VERSION 5.8 ;
BUSBITCHARS "[]" ;
DIVIDERCHAR "/" ;
UNITS
    DATABASE MICRONS 1000 ;
END UNITS

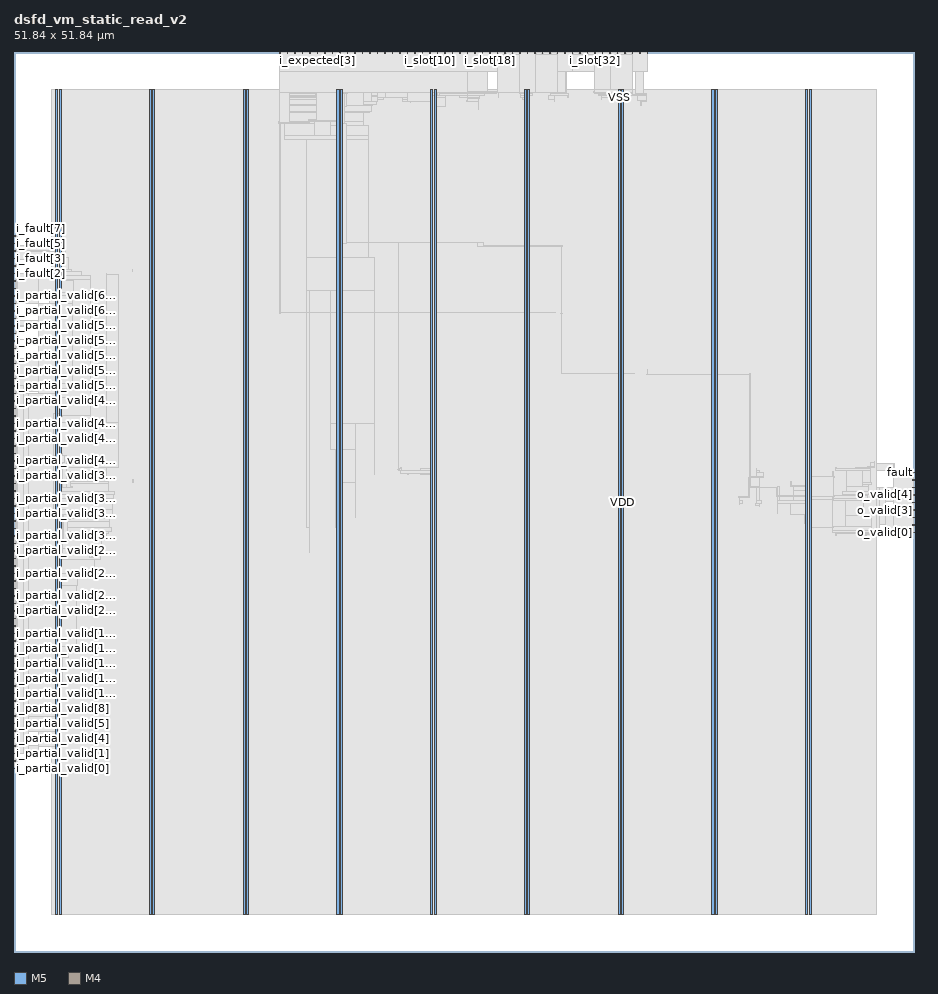
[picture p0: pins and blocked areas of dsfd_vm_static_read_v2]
MACRO dsfd_vm_static_read_v2
  FOREIGN dsfd_vm_static_read_v2 0 0 ;
  CLASS BLOCK ;
  SIZE 51.84 BY 51.84 ;
  PIN ck
    DIRECTION INPUT ;
    USE SIGNAL ;
    PORT
      LAYER M5 ;
        RECT  15.312 51.756 15.336 51.84 ;
    END
  END ck
  PIN fault
    DIRECTION OUTPUT ;
    USE SIGNAL ;
    PORT
      LAYER M4 ;
        RECT  51.756 27.6 51.84 27.624 ;
    END
  END fault
  PIN i_expected[0]
    DIRECTION INPUT ;
    USE SIGNAL ;
    PORT
      LAYER M5 ;
        RECT  16.176 51.756 16.2 51.84 ;
    END
  END i_expected[0]
  PIN i_expected[1]
    DIRECTION INPUT ;
    USE SIGNAL ;
    PORT
      LAYER M5 ;
        RECT  16.608 51.756 16.632 51.84 ;
    END
  END i_expected[1]
  PIN i_expected[2]
    DIRECTION INPUT ;
    USE SIGNAL ;
    PORT
      LAYER M5 ;
        RECT  17.04 51.756 17.064 51.84 ;
    END
  END i_expected[2]
  PIN i_expected[3]
    DIRECTION INPUT ;
    USE SIGNAL ;
    PORT
      LAYER M5 ;
        RECT  17.472 51.756 17.496 51.84 ;
    END
  END i_expected[3]
  PIN i_expected[4]
    DIRECTION INPUT ;
    USE SIGNAL ;
    PORT
      LAYER M5 ;
        RECT  17.904 51.756 17.928 51.84 ;
    END
  END i_expected[4]
  PIN i_expected[5]
    DIRECTION INPUT ;
    USE SIGNAL ;
    PORT
      LAYER M5 ;
        RECT  18.336 51.756 18.36 51.84 ;
    END
  END i_expected[5]
  PIN i_expected[6]
    DIRECTION INPUT ;
    USE SIGNAL ;
    PORT
      LAYER M5 ;
        RECT  18.768 51.756 18.792 51.84 ;
    END
  END i_expected[6]
  PIN i_expected[7]
    DIRECTION INPUT ;
    USE SIGNAL ;
    PORT
      LAYER M5 ;
        RECT  19.2 51.756 19.224 51.84 ;
    END
  END i_expected[7]
  PIN i_fault[0]
    DIRECTION INPUT ;
    USE SIGNAL ;
    PORT
      LAYER M4 ;
        RECT  0 38.208 0.084 38.232 ;
    END
  END i_fault[0]
  PIN i_fault[1]
    DIRECTION INPUT ;
    USE SIGNAL ;
    PORT
      LAYER M4 ;
        RECT  0 38.64 0.084 38.664 ;
    END
  END i_fault[1]
  PIN i_fault[2]
    DIRECTION INPUT ;
    USE SIGNAL ;
    PORT
      LAYER M4 ;
        RECT  0 39.072 0.084 39.096 ;
    END
  END i_fault[2]
  PIN i_fault[3]
    DIRECTION INPUT ;
    USE SIGNAL ;
    PORT
      LAYER M4 ;
        RECT  0 39.504 0.084 39.528 ;
    END
  END i_fault[3]
  PIN i_fault[4]
    DIRECTION INPUT ;
    USE SIGNAL ;
    PORT
      LAYER M4 ;
        RECT  0 39.936 0.084 39.96 ;
    END
  END i_fault[4]
  PIN i_fault[5]
    DIRECTION INPUT ;
    USE SIGNAL ;
    PORT
      LAYER M4 ;
        RECT  0 40.368 0.084 40.392 ;
    END
  END i_fault[5]
  PIN i_fault[6]
    DIRECTION INPUT ;
    USE SIGNAL ;
    PORT
      LAYER M4 ;
        RECT  0 40.8 0.084 40.824 ;
    END
  END i_fault[6]
  PIN i_fault[7]
    DIRECTION INPUT ;
    USE SIGNAL ;
    PORT
      LAYER M4 ;
        RECT  0 41.232 0.084 41.256 ;
    END
  END i_fault[7]
  PIN i_partial_valid[0]
    DIRECTION INPUT ;
    USE SIGNAL ;
    PORT
      LAYER M4 ;
        RECT  0 10.56 0.084 10.584 ;
    END
  END i_partial_valid[0]
  PIN i_partial_valid[10]
    DIRECTION INPUT ;
    USE SIGNAL ;
    PORT
      LAYER M4 ;
        RECT  0 14.88 0.084 14.904 ;
    END
  END i_partial_valid[10]
  PIN i_partial_valid[11]
    DIRECTION INPUT ;
    USE SIGNAL ;
    PORT
      LAYER M4 ;
        RECT  0 15.312 0.084 15.336 ;
    END
  END i_partial_valid[11]
  PIN i_partial_valid[12]
    DIRECTION INPUT ;
    USE SIGNAL ;
    PORT
      LAYER M4 ;
        RECT  0 15.744 0.084 15.768 ;
    END
  END i_partial_valid[12]
  PIN i_partial_valid[13]
    DIRECTION INPUT ;
    USE SIGNAL ;
    PORT
      LAYER M4 ;
        RECT  0 16.176 0.084 16.2 ;
    END
  END i_partial_valid[13]
  PIN i_partial_valid[14]
    DIRECTION INPUT ;
    USE SIGNAL ;
    PORT
      LAYER M4 ;
        RECT  0 16.608 0.084 16.632 ;
    END
  END i_partial_valid[14]
  PIN i_partial_valid[15]
    DIRECTION INPUT ;
    USE SIGNAL ;
    PORT
      LAYER M4 ;
        RECT  0 17.04 0.084 17.064 ;
    END
  END i_partial_valid[15]
  PIN i_partial_valid[16]
    DIRECTION INPUT ;
    USE SIGNAL ;
    PORT
      LAYER M4 ;
        RECT  0 17.472 0.084 17.496 ;
    END
  END i_partial_valid[16]
  PIN i_partial_valid[17]
    DIRECTION INPUT ;
    USE SIGNAL ;
    PORT
      LAYER M4 ;
        RECT  0 17.904 0.084 17.928 ;
    END
  END i_partial_valid[17]
  PIN i_partial_valid[18]
    DIRECTION INPUT ;
    USE SIGNAL ;
    PORT
      LAYER M4 ;
        RECT  0 18.336 0.084 18.36 ;
    END
  END i_partial_valid[18]
  PIN i_partial_valid[19]
    DIRECTION INPUT ;
    USE SIGNAL ;
    PORT
      LAYER M4 ;
        RECT  0 18.768 0.084 18.792 ;
    END
  END i_partial_valid[19]
  PIN i_partial_valid[1]
    DIRECTION INPUT ;
    USE SIGNAL ;
    PORT
      LAYER M4 ;
        RECT  0 10.992 0.084 11.016 ;
    END
  END i_partial_valid[1]
  PIN i_partial_valid[20]
    DIRECTION INPUT ;
    USE SIGNAL ;
    PORT
      LAYER M4 ;
        RECT  0 19.2 0.084 19.224 ;
    END
  END i_partial_valid[20]
  PIN i_partial_valid[21]
    DIRECTION INPUT ;
    USE SIGNAL ;
    PORT
      LAYER M4 ;
        RECT  0 19.632 0.084 19.656 ;
    END
  END i_partial_valid[21]
  PIN i_partial_valid[22]
    DIRECTION INPUT ;
    USE SIGNAL ;
    PORT
      LAYER M4 ;
        RECT  0 20.064 0.084 20.088 ;
    END
  END i_partial_valid[22]
  PIN i_partial_valid[23]
    DIRECTION INPUT ;
    USE SIGNAL ;
    PORT
      LAYER M4 ;
        RECT  0 20.496 0.084 20.52 ;
    END
  END i_partial_valid[23]
  PIN i_partial_valid[24]
    DIRECTION INPUT ;
    USE SIGNAL ;
    PORT
      LAYER M4 ;
        RECT  0 20.928 0.084 20.952 ;
    END
  END i_partial_valid[24]
  PIN i_partial_valid[25]
    DIRECTION INPUT ;
    USE SIGNAL ;
    PORT
      LAYER M4 ;
        RECT  0 21.36 0.084 21.384 ;
    END
  END i_partial_valid[25]
  PIN i_partial_valid[26]
    DIRECTION INPUT ;
    USE SIGNAL ;
    PORT
      LAYER M4 ;
        RECT  0 21.792 0.084 21.816 ;
    END
  END i_partial_valid[26]
  PIN i_partial_valid[27]
    DIRECTION INPUT ;
    USE SIGNAL ;
    PORT
      LAYER M4 ;
        RECT  0 22.224 0.084 22.248 ;
    END
  END i_partial_valid[27]
  PIN i_partial_valid[28]
    DIRECTION INPUT ;
    USE SIGNAL ;
    PORT
      LAYER M4 ;
        RECT  0 22.656 0.084 22.68 ;
    END
  END i_partial_valid[28]
  PIN i_partial_valid[29]
    DIRECTION INPUT ;
    USE SIGNAL ;
    PORT
      LAYER M4 ;
        RECT  0 23.088 0.084 23.112 ;
    END
  END i_partial_valid[29]
  PIN i_partial_valid[2]
    DIRECTION INPUT ;
    USE SIGNAL ;
    PORT
      LAYER M4 ;
        RECT  0 11.424 0.084 11.448 ;
    END
  END i_partial_valid[2]
  PIN i_partial_valid[30]
    DIRECTION INPUT ;
    USE SIGNAL ;
    PORT
      LAYER M4 ;
        RECT  0 23.52 0.084 23.544 ;
    END
  END i_partial_valid[30]
  PIN i_partial_valid[31]
    DIRECTION INPUT ;
    USE SIGNAL ;
    PORT
      LAYER M4 ;
        RECT  0 23.952 0.084 23.976 ;
    END
  END i_partial_valid[31]
  PIN i_partial_valid[32]
    DIRECTION INPUT ;
    USE SIGNAL ;
    PORT
      LAYER M4 ;
        RECT  0 24.384 0.084 24.408 ;
    END
  END i_partial_valid[32]
  PIN i_partial_valid[33]
    DIRECTION INPUT ;
    USE SIGNAL ;
    PORT
      LAYER M4 ;
        RECT  0 24.816 0.084 24.84 ;
    END
  END i_partial_valid[33]
  PIN i_partial_valid[34]
    DIRECTION INPUT ;
    USE SIGNAL ;
    PORT
      LAYER M4 ;
        RECT  0 25.248 0.084 25.272 ;
    END
  END i_partial_valid[34]
  PIN i_partial_valid[35]
    DIRECTION INPUT ;
    USE SIGNAL ;
    PORT
      LAYER M4 ;
        RECT  0 25.68 0.084 25.704 ;
    END
  END i_partial_valid[35]
  PIN i_partial_valid[36]
    DIRECTION INPUT ;
    USE SIGNAL ;
    PORT
      LAYER M4 ;
        RECT  0 26.112 0.084 26.136 ;
    END
  END i_partial_valid[36]
  PIN i_partial_valid[37]
    DIRECTION INPUT ;
    USE SIGNAL ;
    PORT
      LAYER M4 ;
        RECT  0 26.544 0.084 26.568 ;
    END
  END i_partial_valid[37]
  PIN i_partial_valid[38]
    DIRECTION INPUT ;
    USE SIGNAL ;
    PORT
      LAYER M4 ;
        RECT  0 26.976 0.084 27 ;
    END
  END i_partial_valid[38]
  PIN i_partial_valid[39]
    DIRECTION INPUT ;
    USE SIGNAL ;
    PORT
      LAYER M4 ;
        RECT  0 27.408 0.084 27.432 ;
    END
  END i_partial_valid[39]
  PIN i_partial_valid[3]
    DIRECTION INPUT ;
    USE SIGNAL ;
    PORT
      LAYER M4 ;
        RECT  0 11.856 0.084 11.88 ;
    END
  END i_partial_valid[3]
  PIN i_partial_valid[40]
    DIRECTION INPUT ;
    USE SIGNAL ;
    PORT
      LAYER M4 ;
        RECT  0 27.84 0.084 27.864 ;
    END
  END i_partial_valid[40]
  PIN i_partial_valid[41]
    DIRECTION INPUT ;
    USE SIGNAL ;
    PORT
      LAYER M4 ;
        RECT  0 28.272 0.084 28.296 ;
    END
  END i_partial_valid[41]
  PIN i_partial_valid[42]
    DIRECTION INPUT ;
    USE SIGNAL ;
    PORT
      LAYER M4 ;
        RECT  0 28.704 0.084 28.728 ;
    END
  END i_partial_valid[42]
  PIN i_partial_valid[43]
    DIRECTION INPUT ;
    USE SIGNAL ;
    PORT
      LAYER M4 ;
        RECT  0 29.136 0.084 29.16 ;
    END
  END i_partial_valid[43]
  PIN i_partial_valid[44]
    DIRECTION INPUT ;
    USE SIGNAL ;
    PORT
      LAYER M4 ;
        RECT  0 29.568 0.084 29.592 ;
    END
  END i_partial_valid[44]
  PIN i_partial_valid[45]
    DIRECTION INPUT ;
    USE SIGNAL ;
    PORT
      LAYER M4 ;
        RECT  0 30 0.084 30.024 ;
    END
  END i_partial_valid[45]
  PIN i_partial_valid[46]
    DIRECTION INPUT ;
    USE SIGNAL ;
    PORT
      LAYER M4 ;
        RECT  0 30.432 0.084 30.456 ;
    END
  END i_partial_valid[46]
  PIN i_partial_valid[47]
    DIRECTION INPUT ;
    USE SIGNAL ;
    PORT
      LAYER M4 ;
        RECT  0 30.864 0.084 30.888 ;
    END
  END i_partial_valid[47]
  PIN i_partial_valid[48]
    DIRECTION INPUT ;
    USE SIGNAL ;
    PORT
      LAYER M4 ;
        RECT  0 31.296 0.084 31.32 ;
    END
  END i_partial_valid[48]
  PIN i_partial_valid[49]
    DIRECTION INPUT ;
    USE SIGNAL ;
    PORT
      LAYER M4 ;
        RECT  0 31.728 0.084 31.752 ;
    END
  END i_partial_valid[49]
  PIN i_partial_valid[4]
    DIRECTION INPUT ;
    USE SIGNAL ;
    PORT
      LAYER M4 ;
        RECT  0 12.288 0.084 12.312 ;
    END
  END i_partial_valid[4]
  PIN i_partial_valid[50]
    DIRECTION INPUT ;
    USE SIGNAL ;
    PORT
      LAYER M4 ;
        RECT  0 32.16 0.084 32.184 ;
    END
  END i_partial_valid[50]
  PIN i_partial_valid[51]
    DIRECTION INPUT ;
    USE SIGNAL ;
    PORT
      LAYER M4 ;
        RECT  0 32.592 0.084 32.616 ;
    END
  END i_partial_valid[51]
  PIN i_partial_valid[52]
    DIRECTION INPUT ;
    USE SIGNAL ;
    PORT
      LAYER M4 ;
        RECT  0 33.024 0.084 33.048 ;
    END
  END i_partial_valid[52]
  PIN i_partial_valid[53]
    DIRECTION INPUT ;
    USE SIGNAL ;
    PORT
      LAYER M4 ;
        RECT  0 33.456 0.084 33.48 ;
    END
  END i_partial_valid[53]
  PIN i_partial_valid[54]
    DIRECTION INPUT ;
    USE SIGNAL ;
    PORT
      LAYER M4 ;
        RECT  0 33.888 0.084 33.912 ;
    END
  END i_partial_valid[54]
  PIN i_partial_valid[55]
    DIRECTION INPUT ;
    USE SIGNAL ;
    PORT
      LAYER M4 ;
        RECT  0 34.32 0.084 34.344 ;
    END
  END i_partial_valid[55]
  PIN i_partial_valid[56]
    DIRECTION INPUT ;
    USE SIGNAL ;
    PORT
      LAYER M4 ;
        RECT  0 34.752 0.084 34.776 ;
    END
  END i_partial_valid[56]
  PIN i_partial_valid[57]
    DIRECTION INPUT ;
    USE SIGNAL ;
    PORT
      LAYER M4 ;
        RECT  0 35.184 0.084 35.208 ;
    END
  END i_partial_valid[57]
  PIN i_partial_valid[58]
    DIRECTION INPUT ;
    USE SIGNAL ;
    PORT
      LAYER M4 ;
        RECT  0 35.616 0.084 35.64 ;
    END
  END i_partial_valid[58]
  PIN i_partial_valid[59]
    DIRECTION INPUT ;
    USE SIGNAL ;
    PORT
      LAYER M4 ;
        RECT  0 36.048 0.084 36.072 ;
    END
  END i_partial_valid[59]
  PIN i_partial_valid[5]
    DIRECTION INPUT ;
    USE SIGNAL ;
    PORT
      LAYER M4 ;
        RECT  0 12.72 0.084 12.744 ;
    END
  END i_partial_valid[5]
  PIN i_partial_valid[60]
    DIRECTION INPUT ;
    USE SIGNAL ;
    PORT
      LAYER M4 ;
        RECT  0 36.48 0.084 36.504 ;
    END
  END i_partial_valid[60]
  PIN i_partial_valid[61]
    DIRECTION INPUT ;
    USE SIGNAL ;
    PORT
      LAYER M4 ;
        RECT  0 36.912 0.084 36.936 ;
    END
  END i_partial_valid[61]
  PIN i_partial_valid[62]
    DIRECTION INPUT ;
    USE SIGNAL ;
    PORT
      LAYER M4 ;
        RECT  0 37.344 0.084 37.368 ;
    END
  END i_partial_valid[62]
  PIN i_partial_valid[63]
    DIRECTION INPUT ;
    USE SIGNAL ;
    PORT
      LAYER M4 ;
        RECT  0 37.776 0.084 37.8 ;
    END
  END i_partial_valid[63]
  PIN i_partial_valid[6]
    DIRECTION INPUT ;
    USE SIGNAL ;
    PORT
      LAYER M4 ;
        RECT  0 13.152 0.084 13.176 ;
    END
  END i_partial_valid[6]
  PIN i_partial_valid[7]
    DIRECTION INPUT ;
    USE SIGNAL ;
    PORT
      LAYER M4 ;
        RECT  0 13.584 0.084 13.608 ;
    END
  END i_partial_valid[7]
  PIN i_partial_valid[8]
    DIRECTION INPUT ;
    USE SIGNAL ;
    PORT
      LAYER M4 ;
        RECT  0 14.016 0.084 14.04 ;
    END
  END i_partial_valid[8]
  PIN i_partial_valid[9]
    DIRECTION INPUT ;
    USE SIGNAL ;
    PORT
      LAYER M4 ;
        RECT  0 14.448 0.084 14.472 ;
    END
  END i_partial_valid[9]
  PIN i_slot[0]
    DIRECTION INPUT ;
    USE SIGNAL ;
    PORT
      LAYER M5 ;
        RECT  19.632 51.756 19.656 51.84 ;
    END
  END i_slot[0]
  PIN i_slot[10]
    DIRECTION INPUT ;
    USE SIGNAL ;
    PORT
      LAYER M5 ;
        RECT  23.952 51.756 23.976 51.84 ;
    END
  END i_slot[10]
  PIN i_slot[11]
    DIRECTION INPUT ;
    USE SIGNAL ;
    PORT
      LAYER M5 ;
        RECT  24.384 51.756 24.408 51.84 ;
    END
  END i_slot[11]
  PIN i_slot[12]
    DIRECTION INPUT ;
    USE SIGNAL ;
    PORT
      LAYER M5 ;
        RECT  24.816 51.756 24.84 51.84 ;
    END
  END i_slot[12]
  PIN i_slot[13]
    DIRECTION INPUT ;
    USE SIGNAL ;
    PORT
      LAYER M5 ;
        RECT  25.248 51.756 25.272 51.84 ;
    END
  END i_slot[13]
  PIN i_slot[14]
    DIRECTION INPUT ;
    USE SIGNAL ;
    PORT
      LAYER M5 ;
        RECT  25.68 51.756 25.704 51.84 ;
    END
  END i_slot[14]
  PIN i_slot[15]
    DIRECTION INPUT ;
    USE SIGNAL ;
    PORT
      LAYER M5 ;
        RECT  26.112 51.756 26.136 51.84 ;
    END
  END i_slot[15]
  PIN i_slot[16]
    DIRECTION INPUT ;
    USE SIGNAL ;
    PORT
      LAYER M5 ;
        RECT  26.544 51.756 26.568 51.84 ;
    END
  END i_slot[16]
  PIN i_slot[17]
    DIRECTION INPUT ;
    USE SIGNAL ;
    PORT
      LAYER M5 ;
        RECT  26.976 51.756 27 51.84 ;
    END
  END i_slot[17]
  PIN i_slot[18]
    DIRECTION INPUT ;
    USE SIGNAL ;
    PORT
      LAYER M5 ;
        RECT  27.408 51.756 27.432 51.84 ;
    END
  END i_slot[18]
  PIN i_slot[19]
    DIRECTION INPUT ;
    USE SIGNAL ;
    PORT
      LAYER M5 ;
        RECT  27.84 51.756 27.864 51.84 ;
    END
  END i_slot[19]
  PIN i_slot[1]
    DIRECTION INPUT ;
    USE SIGNAL ;
    PORT
      LAYER M5 ;
        RECT  20.064 51.756 20.088 51.84 ;
    END
  END i_slot[1]
  PIN i_slot[20]
    DIRECTION INPUT ;
    USE SIGNAL ;
    PORT
      LAYER M5 ;
        RECT  28.272 51.756 28.296 51.84 ;
    END
  END i_slot[20]
  PIN i_slot[21]
    DIRECTION INPUT ;
    USE SIGNAL ;
    PORT
      LAYER M5 ;
        RECT  28.704 51.756 28.728 51.84 ;
    END
  END i_slot[21]
  PIN i_slot[22]
    DIRECTION INPUT ;
    USE SIGNAL ;
    PORT
      LAYER M5 ;
        RECT  29.136 51.756 29.16 51.84 ;
    END
  END i_slot[22]
  PIN i_slot[23]
    DIRECTION INPUT ;
    USE SIGNAL ;
    PORT
      LAYER M5 ;
        RECT  29.568 51.756 29.592 51.84 ;
    END
  END i_slot[23]
  PIN i_slot[24]
    DIRECTION INPUT ;
    USE SIGNAL ;
    PORT
      LAYER M5 ;
        RECT  30 51.756 30.024 51.84 ;
    END
  END i_slot[24]
  PIN i_slot[25]
    DIRECTION INPUT ;
    USE SIGNAL ;
    PORT
      LAYER M5 ;
        RECT  30.432 51.756 30.456 51.84 ;
    END
  END i_slot[25]
  PIN i_slot[26]
    DIRECTION INPUT ;
    USE SIGNAL ;
    PORT
      LAYER M5 ;
        RECT  30.864 51.756 30.888 51.84 ;
    END
  END i_slot[26]
  PIN i_slot[27]
    DIRECTION INPUT ;
    USE SIGNAL ;
    PORT
      LAYER M5 ;
        RECT  31.296 51.756 31.32 51.84 ;
    END
  END i_slot[27]
  PIN i_slot[28]
    DIRECTION INPUT ;
    USE SIGNAL ;
    PORT
      LAYER M5 ;
        RECT  31.728 51.756 31.752 51.84 ;
    END
  END i_slot[28]
  PIN i_slot[29]
    DIRECTION INPUT ;
    USE SIGNAL ;
    PORT
      LAYER M5 ;
        RECT  32.16 51.756 32.184 51.84 ;
    END
  END i_slot[29]
  PIN i_slot[2]
    DIRECTION INPUT ;
    USE SIGNAL ;
    PORT
      LAYER M5 ;
        RECT  20.496 51.756 20.52 51.84 ;
    END
  END i_slot[2]
  PIN i_slot[30]
    DIRECTION INPUT ;
    USE SIGNAL ;
    PORT
      LAYER M5 ;
        RECT  32.592 51.756 32.616 51.84 ;
    END
  END i_slot[30]
  PIN i_slot[31]
    DIRECTION INPUT ;
    USE SIGNAL ;
    PORT
      LAYER M5 ;
        RECT  33.024 51.756 33.048 51.84 ;
    END
  END i_slot[31]
  PIN i_slot[32]
    DIRECTION INPUT ;
    USE SIGNAL ;
    PORT
      LAYER M5 ;
        RECT  33.456 51.756 33.48 51.84 ;
    END
  END i_slot[32]
  PIN i_slot[33]
    DIRECTION INPUT ;
    USE SIGNAL ;
    PORT
      LAYER M5 ;
        RECT  33.888 51.756 33.912 51.84 ;
    END
  END i_slot[33]
  PIN i_slot[34]
    DIRECTION INPUT ;
    USE SIGNAL ;
    PORT
      LAYER M5 ;
        RECT  34.32 51.756 34.344 51.84 ;
    END
  END i_slot[34]
  PIN i_slot[35]
    DIRECTION INPUT ;
    USE SIGNAL ;
    PORT
      LAYER M5 ;
        RECT  34.752 51.756 34.776 51.84 ;
    END
  END i_slot[35]
  PIN i_slot[36]
    DIRECTION INPUT ;
    USE SIGNAL ;
    PORT
      LAYER M5 ;
        RECT  35.184 51.756 35.208 51.84 ;
    END
  END i_slot[36]
  PIN i_slot[37]
    DIRECTION INPUT ;
    USE SIGNAL ;
    PORT
      LAYER M5 ;
        RECT  35.616 51.756 35.64 51.84 ;
    END
  END i_slot[37]
  PIN i_slot[38]
    DIRECTION INPUT ;
    USE SIGNAL ;
    PORT
      LAYER M5 ;
        RECT  36.048 51.756 36.072 51.84 ;
    END
  END i_slot[38]
  PIN i_slot[39]
    DIRECTION INPUT ;
    USE SIGNAL ;
    PORT
      LAYER M5 ;
        RECT  36.48 51.756 36.504 51.84 ;
    END
  END i_slot[39]
  PIN i_slot[3]
    DIRECTION INPUT ;
    USE SIGNAL ;
    PORT
      LAYER M5 ;
        RECT  20.928 51.756 20.952 51.84 ;
    END
  END i_slot[3]
  PIN i_slot[4]
    DIRECTION INPUT ;
    USE SIGNAL ;
    PORT
      LAYER M5 ;
        RECT  21.36 51.756 21.384 51.84 ;
    END
  END i_slot[4]
  PIN i_slot[5]
    DIRECTION INPUT ;
    USE SIGNAL ;
    PORT
      LAYER M5 ;
        RECT  21.792 51.756 21.816 51.84 ;
    END
  END i_slot[5]
  PIN i_slot[6]
    DIRECTION INPUT ;
    USE SIGNAL ;
    PORT
      LAYER M5 ;
        RECT  22.224 51.756 22.248 51.84 ;
    END
  END i_slot[6]
  PIN i_slot[7]
    DIRECTION INPUT ;
    USE SIGNAL ;
    PORT
      LAYER M5 ;
        RECT  22.656 51.756 22.68 51.84 ;
    END
  END i_slot[7]
  PIN i_slot[8]
    DIRECTION INPUT ;
    USE SIGNAL ;
    PORT
      LAYER M5 ;
        RECT  23.088 51.756 23.112 51.84 ;
    END
  END i_slot[8]
  PIN i_slot[9]
    DIRECTION INPUT ;
    USE SIGNAL ;
    PORT
      LAYER M5 ;
        RECT  23.52 51.756 23.544 51.84 ;
    END
  END i_slot[9]
  PIN o_valid[0]
    DIRECTION OUTPUT ;
    USE SIGNAL ;
    PORT
      LAYER M4 ;
        RECT  51.756 24.144 51.84 24.168 ;
    END
  END o_valid[0]
  PIN o_valid[1]
    DIRECTION OUTPUT ;
    USE SIGNAL ;
    PORT
      LAYER M4 ;
        RECT  51.756 24.576 51.84 24.6 ;
    END
  END o_valid[1]
  PIN o_valid[2]
    DIRECTION OUTPUT ;
    USE SIGNAL ;
    PORT
      LAYER M4 ;
        RECT  51.756 25.008 51.84 25.032 ;
    END
  END o_valid[2]
  PIN o_valid[3]
    DIRECTION OUTPUT ;
    USE SIGNAL ;
    PORT
      LAYER M4 ;
        RECT  51.756 25.44 51.84 25.464 ;
    END
  END o_valid[3]
  PIN o_valid[4]
    DIRECTION OUTPUT ;
    USE SIGNAL ;
    PORT
      LAYER M4 ;
        RECT  51.756 25.872 51.84 25.896 ;
    END
  END o_valid[4]
  PIN o_valid[5]
    DIRECTION OUTPUT ;
    USE SIGNAL ;
    PORT
      LAYER M4 ;
        RECT  51.756 26.304 51.84 26.328 ;
    END
  END o_valid[5]
  PIN o_valid[6]
    DIRECTION OUTPUT ;
    USE SIGNAL ;
    PORT
      LAYER M4 ;
        RECT  51.756 26.736 51.84 26.76 ;
    END
  END o_valid[6]
  PIN o_valid[7]
    DIRECTION OUTPUT ;
    USE SIGNAL ;
    PORT
      LAYER M4 ;
        RECT  51.756 27.168 51.84 27.192 ;
    END
  END o_valid[7]
  PIN rst_n
    DIRECTION INPUT ;
    USE SIGNAL ;
    PORT
      LAYER M5 ;
        RECT  15.744 51.756 15.768 51.84 ;
    END
  END rst_n
  PIN VDD
    DIRECTION INOUT ;
    USE POWER ;
    PORT
      LAYER M5 ;
        RECT  45.792 2.151 45.912 49.689 ;
        RECT  40.392 2.151 40.512 49.689 ;
        RECT  34.992 2.151 35.112 49.689 ;
        RECT  29.592 2.151 29.712 49.689 ;
        RECT  24.192 2.151 24.312 49.689 ;
        RECT  18.792 2.151 18.912 49.689 ;
        RECT  13.392 2.151 13.512 49.689 ;
        RECT  7.992 2.151 8.112 49.689 ;
        RECT  2.592 2.151 2.712 49.689 ;
    END
  END VDD
  PIN VSS
    DIRECTION INOUT ;
    USE GROUND ;
    PORT
      LAYER M5 ;
        RECT  45.6 2.137 45.72 49.703 ;
        RECT  40.2 2.137 40.32 49.703 ;
        RECT  34.8 2.137 34.92 49.703 ;
        RECT  29.4 2.137 29.52 49.703 ;
        RECT  24 2.137 24.12 49.703 ;
        RECT  18.6 2.137 18.72 49.703 ;
        RECT  13.2 2.137 13.32 49.703 ;
        RECT  7.8 2.137 7.92 49.703 ;
        RECT  2.4 2.137 2.52 49.703 ;
    END
  END VSS
  # OT_OBS_CLOSED layer=M5 d_um=1.536 added=23
  OBS
    LAYER RVTN ;
     RECT  2.16 2.16 49.68 2.295 ;
     RECT  2.16 2.565 49.68 2.835 ;
     RECT  2.16 3.105 49.68 3.375 ;
     RECT  2.16 3.645 49.68 3.915 ;
     RECT  2.16 4.185 49.68 4.455 ;
     RECT  2.16 4.725 49.68 4.995 ;
     RECT  2.16 5.265 49.68 5.535 ;
     RECT  2.16 5.805 49.68 6.075 ;
     RECT  2.16 6.345 49.68 6.615 ;
     RECT  2.16 6.885 49.68 7.155 ;
     RECT  2.16 7.425 49.68 7.695 ;
     RECT  2.16 7.965 49.68 8.235 ;
     RECT  2.16 8.505 49.68 8.775 ;
     RECT  2.16 9.045 49.68 9.315 ;
     RECT  2.16 9.585 49.68 9.855 ;
     RECT  2.16 10.125 49.68 10.395 ;
     RECT  2.16 10.665 49.68 10.935 ;
     RECT  2.16 11.205 49.68 11.475 ;
     RECT  2.16 11.745 49.68 12.015 ;
     RECT  2.16 12.285 49.68 12.555 ;
     RECT  2.16 12.825 49.68 13.095 ;
     RECT  2.16 13.365 49.68 13.635 ;
     RECT  2.16 13.905 49.68 14.175 ;
     RECT  2.16 14.445 49.68 14.715 ;
     RECT  2.16 14.985 49.68 15.255 ;
     RECT  2.16 15.525 49.68 15.795 ;
     RECT  2.16 16.065 49.68 16.335 ;
     RECT  2.16 16.605 49.68 16.875 ;
     RECT  2.16 17.145 49.68 17.415 ;
     RECT  2.16 17.685 49.68 17.955 ;
     RECT  2.16 18.225 49.68 18.495 ;
     RECT  2.16 18.765 49.68 19.035 ;
     RECT  2.16 19.305 49.68 19.575 ;
     RECT  2.16 19.845 49.68 20.115 ;
     RECT  2.16 20.385 49.68 20.655 ;
     RECT  2.16 20.925 49.68 21.195 ;
     RECT  2.16 21.465 49.68 21.735 ;
     RECT  2.16 22.005 49.68 22.275 ;
     RECT  2.16 22.545 49.68 22.815 ;
     RECT  2.16 23.085 49.68 23.355 ;
     RECT  2.16 23.625 49.68 23.895 ;
     RECT  2.16 24.165 49.68 24.435 ;
     RECT  2.16 24.705 49.68 24.975 ;
     RECT  2.16 25.245 49.68 25.515 ;
     RECT  2.16 25.785 49.68 26.055 ;
     RECT  2.16 26.325 49.68 26.595 ;
     RECT  2.16 26.865 49.68 27.135 ;
     RECT  2.16 27.405 49.68 27.675 ;
     RECT  2.16 27.945 49.68 28.215 ;
     RECT  2.16 28.485 49.68 28.755 ;
     RECT  2.16 29.025 49.68 29.295 ;
     RECT  2.16 29.565 49.68 29.835 ;
     RECT  2.16 30.105 49.68 30.375 ;
     RECT  2.16 30.645 49.68 30.915 ;
     RECT  2.16 31.185 49.68 31.455 ;
     RECT  2.16 31.725 49.68 31.995 ;
     RECT  2.16 32.265 49.68 32.535 ;
     RECT  2.16 32.805 49.68 33.075 ;
     RECT  2.16 33.345 49.68 33.615 ;
     RECT  2.16 33.885 49.68 34.155 ;
     RECT  2.16 34.425 49.68 34.695 ;
     RECT  2.16 34.965 49.68 35.235 ;
     RECT  2.16 35.505 49.68 35.775 ;
     RECT  2.16 36.045 49.68 36.315 ;
     RECT  2.16 36.585 49.68 36.855 ;
     RECT  2.16 37.125 49.68 37.395 ;
     RECT  2.16 37.665 49.68 37.935 ;
     RECT  2.16 38.205 49.68 38.475 ;
     RECT  2.16 38.745 49.68 39.015 ;
     RECT  2.16 39.285 49.68 39.555 ;
     RECT  2.16 39.825 49.68 40.095 ;
     RECT  2.16 40.365 49.68 40.635 ;
     RECT  2.16 40.905 49.68 41.175 ;
     RECT  2.16 41.445 49.68 41.715 ;
     RECT  2.16 41.985 49.68 42.255 ;
     RECT  2.16 42.525 49.68 42.795 ;
     RECT  2.16 43.065 49.68 43.335 ;
     RECT  2.16 43.605 49.68 43.875 ;
     RECT  2.16 44.145 49.68 44.415 ;
     RECT  2.16 44.685 49.68 44.955 ;
     RECT  2.16 45.225 49.68 45.495 ;
     RECT  2.16 45.765 49.68 46.035 ;
     RECT  2.16 46.305 49.68 46.575 ;
     RECT  2.16 46.845 49.68 47.115 ;
     RECT  2.16 47.385 49.68 47.655 ;
     RECT  2.16 47.925 49.68 48.195 ;
     RECT  2.16 48.465 49.68 48.735 ;
     RECT  2.16 49.005 49.68 49.275 ;
     RECT  2.16 49.545 49.68 49.68 ;
    LAYER RVTP ;
     RECT  2.16 2.295 49.68 2.565 ;
     RECT  2.16 2.835 49.68 3.105 ;
     RECT  2.16 3.375 49.68 3.645 ;
     RECT  2.16 3.915 49.68 4.185 ;
     RECT  2.16 4.455 49.68 4.725 ;
     RECT  2.16 4.995 49.68 5.265 ;
     RECT  2.16 5.535 49.68 5.805 ;
     RECT  2.16 6.075 49.68 6.345 ;
     RECT  2.16 6.615 49.68 6.885 ;
     RECT  2.16 7.155 49.68 7.425 ;
     RECT  2.16 7.695 49.68 7.965 ;
     RECT  2.16 8.235 49.68 8.505 ;
     RECT  2.16 8.775 49.68 9.045 ;
     RECT  2.16 9.315 49.68 9.585 ;
     RECT  2.16 9.855 49.68 10.125 ;
     RECT  2.16 10.395 49.68 10.665 ;
     RECT  2.16 10.935 49.68 11.205 ;
     RECT  2.16 11.475 49.68 11.745 ;
     RECT  2.16 12.015 49.68 12.285 ;
     RECT  2.16 12.555 49.68 12.825 ;
     RECT  2.16 13.095 49.68 13.365 ;
     RECT  2.16 13.635 49.68 13.905 ;
     RECT  2.16 14.175 49.68 14.445 ;
     RECT  2.16 14.715 49.68 14.985 ;
     RECT  2.16 15.255 49.68 15.525 ;
     RECT  2.16 15.795 49.68 16.065 ;
     RECT  2.16 16.335 49.68 16.605 ;
     RECT  2.16 16.875 49.68 17.145 ;
     RECT  2.16 17.415 49.68 17.685 ;
     RECT  2.16 17.955 49.68 18.225 ;
     RECT  2.16 18.495 49.68 18.765 ;
     RECT  2.16 19.035 49.68 19.305 ;
     RECT  2.16 19.575 49.68 19.845 ;
     RECT  2.16 20.115 49.68 20.385 ;
     RECT  2.16 20.655 49.68 20.925 ;
     RECT  2.16 21.195 49.68 21.465 ;
     RECT  2.16 21.735 49.68 22.005 ;
     RECT  2.16 22.275 49.68 22.545 ;
     RECT  2.16 22.815 49.68 23.085 ;
     RECT  2.16 23.355 49.68 23.625 ;
     RECT  2.16 23.895 49.68 24.165 ;
     RECT  2.16 24.435 49.68 24.705 ;
     RECT  2.16 24.975 49.68 25.245 ;
     RECT  2.16 25.515 49.68 25.785 ;
     RECT  2.16 26.055 49.68 26.325 ;
     RECT  2.16 26.595 49.68 26.865 ;
     RECT  2.16 27.135 49.68 27.405 ;
     RECT  2.16 27.675 49.68 27.945 ;
     RECT  2.16 28.215 49.68 28.485 ;
     RECT  2.16 28.755 49.68 29.025 ;
     RECT  2.16 29.295 49.68 29.565 ;
     RECT  2.16 29.835 49.68 30.105 ;
     RECT  2.16 30.375 49.68 30.645 ;
     RECT  2.16 30.915 49.68 31.185 ;
     RECT  2.16 31.455 49.68 31.725 ;
     RECT  2.16 31.995 49.68 32.265 ;
     RECT  2.16 32.535 49.68 32.805 ;
     RECT  2.16 33.075 49.68 33.345 ;
     RECT  2.16 33.615 49.68 33.885 ;
     RECT  2.16 34.155 49.68 34.425 ;
     RECT  2.16 34.695 49.68 34.965 ;
     RECT  2.16 35.235 49.68 35.505 ;
     RECT  2.16 35.775 49.68 36.045 ;
     RECT  2.16 36.315 49.68 36.585 ;
     RECT  2.16 36.855 49.68 37.125 ;
     RECT  2.16 37.395 49.68 37.665 ;
     RECT  2.16 37.935 49.68 38.205 ;
     RECT  2.16 38.475 49.68 38.745 ;
     RECT  2.16 39.015 49.68 39.285 ;
     RECT  2.16 39.555 49.68 39.825 ;
     RECT  2.16 40.095 49.68 40.365 ;
     RECT  2.16 40.635 49.68 40.905 ;
     RECT  2.16 41.175 49.68 41.445 ;
     RECT  2.16 41.715 49.68 41.985 ;
     RECT  2.16 42.255 49.68 42.525 ;
     RECT  2.16 42.795 49.68 43.065 ;
     RECT  2.16 43.335 49.68 43.605 ;
     RECT  2.16 43.875 49.68 44.145 ;
     RECT  2.16 44.415 49.68 44.685 ;
     RECT  2.16 44.955 49.68 45.225 ;
     RECT  2.16 45.495 49.68 45.765 ;
     RECT  2.16 46.035 49.68 46.305 ;
     RECT  2.16 46.575 49.68 46.845 ;
     RECT  2.16 47.115 49.68 47.385 ;
     RECT  2.16 47.655 49.68 47.925 ;
     RECT  2.16 48.195 49.68 48.465 ;
     RECT  2.16 48.735 49.68 49.005 ;
     RECT  2.16 49.275 49.68 49.545 ;
    LAYER M1 ;
     RECT  2.16 2.151 49.68 49.689 ;
    LAYER M2 ;
     RECT  0.067 22.086 0.103 22.104 ;
     RECT  0.031 23.976 0.103 23.994 ;
     RECT  0.031 25.758 0.103 25.776 ;
     RECT  0.103 23.67 0.139 23.994 ;
     RECT  0.103 32.31 0.139 32.328 ;
     RECT  0.103 33.552 0.139 34.182 ;
     RECT  0.103 36.36 0.139 36.378 ;
     RECT  0.103 39.87 0.139 40.086 ;
     RECT  0.103 27.414 0.175 27.432 ;
     RECT  0.139 23.436 0.211 23.994 ;
     RECT  0.103 18.81 0.239 18.828 ;
     RECT  0.175 27.342 0.535 27.432 ;
     RECT  0.103 25.758 0.823 25.848 ;
     RECT  0.823 25.758 1.399 25.884 ;
     RECT  0.103 30.69 1.399 30.708 ;
     RECT  0.139 32.31 1.399 34.182 ;
     RECT  0.535 27.342 1.723 27.738 ;
     RECT  0.535 28.8 1.723 28.818 ;
     RECT  1.399 30.69 1.723 30.87 ;
     RECT  1.723 27.342 1.975 28.818 ;
     RECT  1.723 30.042 2.011 30.87 ;
     RECT  1.399 31.968 2.011 34.182 ;
     RECT  1.507 19.782 2.047 19.8 ;
     RECT  1.435 20.592 2.047 20.61 ;
     RECT  1.975 26.802 2.047 28.818 ;
     RECT  2.011 30.042 2.047 34.182 ;
     RECT  2.083 17.622 2.16 17.64 ;
     RECT  2.047 19.782 2.16 20.61 ;
     RECT  0.103 22.05 2.16 22.104 ;
     RECT  0.211 23.166 2.16 23.994 ;
     RECT  1.399 25.326 2.16 25.884 ;
     RECT  2.047 26.802 2.16 34.182 ;
     RECT  0.103 35.28 2.16 35.298 ;
     RECT  0.139 36.09 2.16 36.378 ;
     RECT  0.103 39.06 2.16 39.078 ;
     RECT  0.139 39.87 2.16 40.698 ;
     RECT  2.16 2.151 49.68 49.689 ;
     RECT  49.68 24.246 49.847 26.784 ;
     RECT  49.847 24.606 50.171 26.784 ;
     RECT  50.171 24.606 50.207 24.804 ;
     RECT  49.68 27.756 50.675 28.134 ;
     RECT  50.207 24.606 50.711 24.624 ;
     RECT  50.171 25.956 50.711 26.784 ;
     RECT  50.675 28.116 50.711 28.134 ;
    LAYER M3 ;
     RECT  2.415 2.143 2.505 2.413 ;
     RECT  7.815 2.143 7.905 2.413 ;
     RECT  13.215 2.143 13.305 2.413 ;
     RECT  18.615 2.143 18.705 2.413 ;
     RECT  24.015 2.143 24.105 2.413 ;
     RECT  29.415 2.143 29.505 2.413 ;
     RECT  34.815 2.143 34.905 2.413 ;
     RECT  40.215 2.143 40.305 2.413 ;
     RECT  45.615 2.143 45.705 2.413 ;
     RECT  0.108 10.555 0.126 10.699 ;
     RECT  0.036 10.699 0.126 10.987 ;
     RECT  0.036 10.987 0.162 11.117 ;
     RECT  2.415 2.413 2.697 11.419 ;
     RECT  1.98 11.419 2.697 11.851 ;
     RECT  0.036 11.117 0.09 12.283 ;
     RECT  0.036 12.283 0.126 12.715 ;
     RECT  1.404 11.851 2.697 12.715 ;
     RECT  0.036 12.715 2.697 15.307 ;
     RECT  0.036 15.307 2.79 16.951 ;
     RECT  0.036 16.951 3.114 17.581 ;
     RECT  0.036 17.581 3.618 21.091 ;
     RECT  4.392 21.505 4.41 21.541 ;
     RECT  0.036 21.091 3.654 21.811 ;
     RECT  4.392 21.541 4.626 21.811 ;
     RECT  0.036 21.811 4.626 22.621 ;
     RECT  0.036 22.621 4.986 23.251 ;
     RECT  0.036 23.251 5.022 23.899 ;
     RECT  48.996 23.791 49.014 23.971 ;
     RECT  0.036 23.899 5.346 23.999 ;
     RECT  48.528 23.971 49.122 24.061 ;
     RECT  0.18 23.999 5.346 24.097 ;
     RECT  47.34 23.971 47.358 24.097 ;
     RECT  48.528 24.061 49.302 24.097 ;
     RECT  47.34 24.097 49.302 24.139 ;
     RECT  47.34 24.139 49.842 24.169 ;
     RECT  0.18 24.097 5.454 24.241 ;
     RECT  47.16 24.169 49.842 24.269 ;
     RECT  17.028 23.017 17.046 24.439 ;
     RECT  0.18 24.241 5.598 24.467 ;
     RECT  18.615 2.413 18.897 24.475 ;
     RECT  47.16 24.269 49.374 24.509 ;
     RECT  50.688 24.571 50.706 24.629 ;
     RECT  45.615 2.413 45.897 24.637 ;
     RECT  45.615 24.637 46.386 24.709 ;
     RECT  45.54 24.709 46.386 24.781 ;
     RECT  0.18 24.467 5.526 24.811 ;
     RECT  45.54 24.781 46.854 24.935 ;
     RECT  0.108 24.811 5.526 24.941 ;
     RECT  50.184 24.781 50.202 25.037 ;
     RECT  47.88 24.509 49.374 25.169 ;
     RECT  0.18 24.941 5.526 25.213 ;
     RECT  44.748 25.177 44.766 25.213 ;
     RECT  45.54 24.935 45.897 25.213 ;
     RECT  46.764 24.935 46.782 25.439 ;
     RECT  50.148 25.411 50.166 25.469 ;
     RECT  0.18 25.213 5.67 25.475 ;
     RECT  42.948 25.681 42.966 25.717 ;
     RECT  0.18 25.475 0.882 25.753 ;
     RECT  42.732 25.717 42.966 25.853 ;
     RECT  41.76 25.789 41.778 25.861 ;
     RECT  42.768 25.853 42.966 25.861 ;
     RECT  43.956 25.249 43.974 25.861 ;
     RECT  44.748 25.213 45.897 25.861 ;
     RECT  43.956 25.861 45.897 25.979 ;
     RECT  47.88 25.169 48.906 26.011 ;
     RECT  41.76 25.861 41.958 26.015 ;
     RECT  42.768 25.861 43.074 26.015 ;
     RECT  47.16 26.011 48.906 26.095 ;
     RECT  1.728 25.475 5.67 26.131 ;
     RECT  41.76 26.015 41.778 26.237 ;
     RECT  44.892 25.979 45.897 26.257 ;
     RECT  47.16 26.095 49.158 26.285 ;
     RECT  44.892 26.257 46.386 26.293 ;
     RECT  1.728 26.131 5.706 26.365 ;
     RECT  47.7 26.285 49.158 26.365 ;
     RECT  1.728 26.365 5.814 26.519 ;
     RECT  47.7 26.365 49.23 26.519 ;
     RECT  44.892 26.293 46.854 26.555 ;
     RECT  43.956 25.979 44.118 26.789 ;
     RECT  50.688 25.867 50.706 26.789 ;
     RECT  44.892 26.555 45.897 26.797 ;
     RECT  47.952 26.519 49.23 26.825 ;
     RECT  42.768 26.015 42.93 26.827 ;
     RECT  44.748 26.797 45.897 26.861 ;
     RECT  48.888 26.825 49.23 26.905 ;
     RECT  0.036 25.753 0.882 26.971 ;
     RECT  1.728 26.519 5.454 26.971 ;
     RECT  48.888 26.905 49.374 27.059 ;
     RECT  18.54 24.475 18.897 27.067 ;
     RECT  19.656 25.015 19.674 27.067 ;
     RECT  0.036 26.971 5.454 27.095 ;
     RECT  44.748 26.861 44.766 27.095 ;
     RECT  6.84 27.031 6.858 27.203 ;
     RECT  42.372 26.827 42.93 27.337 ;
     RECT  42.372 27.337 43.182 27.365 ;
     RECT  24.015 2.413 24.297 27.481 ;
     RECT  22.68 27.481 22.698 27.571 ;
     RECT  23.436 27.481 24.297 27.571 ;
     RECT  50.652 27.163 50.67 27.595 ;
     RECT  0.036 27.095 5.346 27.635 ;
     RECT  42.768 27.365 43.182 27.635 ;
     RECT  47.16 27.355 47.178 27.671 ;
     RECT  22.284 27.571 24.297 27.707 ;
     RECT  42.768 27.635 42.93 27.707 ;
     RECT  47.952 26.825 47.97 27.715 ;
     RECT  23.076 27.707 24.297 27.743 ;
     RECT  22.284 27.707 22.302 27.751 ;
     RECT  47.34 27.715 47.97 27.751 ;
     RECT  48.888 27.059 49.338 27.751 ;
     RECT  50.652 27.595 50.706 27.779 ;
     RECT  22.14 27.751 22.302 27.821 ;
     RECT  23.4 27.743 24.297 27.869 ;
     RECT  42.768 27.707 42.786 27.869 ;
     RECT  47.34 27.751 49.338 27.869 ;
     RECT  22.284 27.821 22.302 27.905 ;
     RECT  47.34 27.869 47.358 27.905 ;
     RECT  48.456 27.869 49.338 27.905 ;
     RECT  1.404 27.635 5.346 27.913 ;
     RECT  49.176 27.905 49.338 27.913 ;
     RECT  49.176 27.913 49.554 27.941 ;
     RECT  50.688 27.779 50.706 28.139 ;
     RECT  49.32 27.941 49.554 28.211 ;
     RECT  49.536 28.211 49.554 28.247 ;
     RECT  18.54 27.067 19.674 28.921 ;
     RECT  0.036 27.635 0.558 29.165 ;
     RECT  18.252 28.921 19.674 30.451 ;
     RECT  20.772 27.481 20.79 30.451 ;
     RECT  1.404 27.913 5.994 30.479 ;
     RECT  1.404 30.479 4.41 30.875 ;
     RECT  1.98 30.875 4.41 31.963 ;
     RECT  1.404 31.963 4.41 32.459 ;
     RECT  0.036 29.165 0.198 32.467 ;
     RECT  0.036 32.467 0.558 32.621 ;
     RECT  1.404 32.459 3.402 32.729 ;
     RECT  34.815 2.413 35.097 33.304 ;
     RECT  34.815 33.304 35.73 33.341 ;
     RECT  36.468 33.241 36.486 33.539 ;
     RECT  0.036 32.621 0.198 34.781 ;
     RECT  0.036 34.781 0.126 35.021 ;
     RECT  0.108 35.021 0.126 36.085 ;
     RECT  0.108 36.085 0.162 36.509 ;
     RECT  31.536 36.751 31.554 36.797 ;
     RECT  31.176 36.811 31.194 36.851 ;
     RECT  0.144 36.509 0.162 36.941 ;
     RECT  1.404 32.729 3.366 37.373 ;
     RECT  2.016 37.373 3.366 37.805 ;
     RECT  2.304 37.805 3.366 38.011 ;
     RECT  16.848 24.439 17.046 38.101 ;
     RECT  18.252 30.451 20.79 38.101 ;
     RECT  2.304 38.011 3.402 38.705 ;
     RECT  2.415 38.705 3.402 38.713 ;
     RECT  4.392 32.459 4.41 38.713 ;
     RECT  2.415 38.713 4.41 38.939 ;
     RECT  5.328 30.479 5.994 39.011 ;
     RECT  5.328 39.011 5.346 39.083 ;
     RECT  2.415 38.939 3.906 39.209 ;
     RECT  2.415 39.209 3.294 39.317 ;
     RECT  6.804 39.217 6.822 39.317 ;
     RECT  2.415 39.317 3.114 40.019 ;
     RECT  16.848 38.101 20.79 40.019 ;
     RECT  2.415 40.019 2.97 40.135 ;
     RECT  2.34 40.135 2.97 40.397 ;
     RECT  2.415 40.397 2.97 40.559 ;
     RECT  0.108 39.055 0.126 40.675 ;
     RECT  26.712 40.651 26.73 40.801 ;
     RECT  0.108 40.675 0.162 40.829 ;
     RECT  26.712 40.801 27.018 40.829 ;
     RECT  27 40.829 27.018 40.877 ;
     RECT  0.144 40.829 0.162 41.261 ;
     RECT  16.848 40.019 20.394 46.777 ;
     RECT  15.588 46.777 15.606 46.813 ;
     RECT  16.704 46.777 20.394 46.813 ;
     RECT  15.588 46.813 20.394 47.039 ;
     RECT  18.252 47.039 20.394 47.579 ;
     RECT  15.588 47.039 17.298 47.731 ;
     RECT  15.228 47.731 17.298 47.837 ;
     RECT  15.372 47.837 17.298 47.849 ;
     RECT  15.732 47.849 17.298 47.857 ;
     RECT  18.252 47.579 20.106 47.857 ;
     RECT  15.732 47.857 20.106 48.361 ;
     RECT  15.732 48.361 20.502 48.397 ;
     RECT  24.015 27.869 24.297 48.703 ;
     RECT  15.732 48.397 20.61 48.739 ;
     RECT  15.732 48.739 20.646 48.811 ;
     RECT  22.824 48.937 22.842 48.973 ;
     RECT  26.748 48.505 26.766 48.973 ;
     RECT  36.108 48.775 36.126 48.973 ;
     RECT  22.716 48.973 22.842 49.009 ;
     RECT  36.108 48.973 36.414 49.045 ;
     RECT  15.732 48.811 20.898 49.081 ;
     RECT  22.392 49.009 22.878 49.081 ;
     RECT  29.415 2.413 29.697 49.081 ;
     RECT  31.14 49.009 31.158 49.081 ;
     RECT  15.732 49.081 21.258 49.109 ;
     RECT  26.1 48.973 26.766 49.171 ;
     RECT  22.392 49.081 22.914 49.207 ;
     RECT  24.015 48.703 24.858 49.207 ;
     RECT  26.1 49.171 26.838 49.207 ;
     RECT  15.804 49.109 21.258 49.237 ;
     RECT  22.392 49.207 24.858 49.243 ;
     RECT  29.304 49.081 29.697 49.243 ;
     RECT  33.84 49.081 33.858 49.243 ;
     RECT  34.815 33.341 35.097 49.243 ;
     RECT  15.804 49.237 21.294 49.277 ;
     RECT  30.78 49.081 31.158 49.307 ;
     RECT  22.212 49.243 24.858 49.315 ;
     RECT  25.632 49.207 26.838 49.315 ;
     RECT  29.196 49.243 29.697 49.315 ;
     RECT  30.924 49.307 31.158 49.315 ;
     RECT  31.896 49.243 31.914 49.315 ;
     RECT  33.84 49.243 35.097 49.315 ;
     RECT  35.928 49.045 36.414 49.315 ;
     RECT  15.804 49.277 21.258 49.343 ;
     RECT  22.212 49.315 26.946 49.351 ;
     RECT  33.66 49.315 36.414 49.373 ;
     RECT  2.415 40.559 2.697 49.427 ;
     RECT  7.815 2.413 8.097 49.427 ;
     RECT  13.215 2.413 13.497 49.427 ;
     RECT  33.66 49.373 35.097 49.427 ;
     RECT  40.215 2.413 40.497 49.427 ;
     RECT  45.615 26.861 45.897 49.427 ;
     RECT  27.9 49.243 27.918 49.469 ;
     RECT  29.196 49.315 29.862 49.469 ;
     RECT  30.924 49.315 31.914 49.469 ;
     RECT  35.82 49.373 36.414 49.469 ;
     RECT  22.212 49.351 27.09 49.477 ;
     RECT  29.196 49.469 29.754 49.477 ;
     RECT  33.66 49.427 34.905 49.477 ;
     RECT  15.804 49.343 21.222 49.517 ;
     RECT  33.408 49.477 34.905 49.517 ;
     RECT  22.212 49.477 27.81 49.531 ;
     RECT  19.908 49.517 21.222 49.541 ;
     RECT  21.996 49.531 27.81 49.565 ;
     RECT  29.088 49.477 29.754 49.565 ;
     RECT  30.924 49.469 31.806 49.565 ;
     RECT  33.408 49.517 33.426 49.565 ;
     RECT  16.164 49.517 16.614 49.577 ;
     RECT  17.46 49.517 18.81 49.577 ;
     RECT  19.908 49.541 20.97 49.577 ;
     RECT  21.996 49.565 22.842 49.577 ;
     RECT  31.5 49.565 31.806 49.577 ;
     RECT  20.952 49.577 20.97 49.649 ;
     RECT  2.415 49.427 2.505 49.697 ;
     RECT  7.815 49.427 7.905 49.697 ;
     RECT  13.215 49.427 13.305 49.697 ;
     RECT  18.615 49.577 18.81 49.697 ;
     RECT  23.976 49.565 24.105 49.697 ;
     RECT  29.34 49.565 29.505 49.697 ;
     RECT  34.815 49.517 34.905 49.697 ;
     RECT  40.215 49.427 40.305 49.697 ;
     RECT  45.615 49.427 45.705 49.697 ;
     RECT  18.792 49.697 18.81 49.805 ;
     RECT  29.34 49.697 29.358 49.805 ;
     RECT  23.976 49.697 23.994 49.853 ;
     RECT  22.212 49.577 22.77 50.765 ;
     RECT  25.524 49.565 27.27 50.765 ;
     RECT  31.788 49.577 31.806 50.765 ;
     RECT  35.82 49.469 36.27 50.765 ;
     RECT  26.604 50.765 26.622 51.677 ;
    LAYER M4 ;
     RECT  0.025 10.704 0.06 10.728 ;
     RECT  0.025 34.992 0.06 35.016 ;
     RECT  0.06 10.56 0.137 41.256 ;
     RECT  0.137 10.992 0.173 33.48 ;
     RECT  0.137 36.048 0.173 39.096 ;
     RECT  0.137 40.368 0.173 41.256 ;
     RECT  0.137 34.752 0.209 34.776 ;
     RECT  0.173 11.424 0.569 32.616 ;
     RECT  0.569 11.424 0.857 32.184 ;
     RECT  0.857 11.424 1.433 11.88 ;
     RECT  0.173 37.344 1.433 39.096 ;
     RECT  1.433 11.424 2.408 11.448 ;
     RECT  0.857 13.584 2.408 32.184 ;
     RECT  0.173 36.048 2.408 36.072 ;
     RECT  1.433 37.776 2.408 39.096 ;
     RECT  0.173 40.368 2.408 40.392 ;
     RECT  2.408 2.148 2.512 49.692 ;
     RECT  2.512 2.418 2.704 49.422 ;
     RECT  2.704 17.904 2.765 17.928 ;
     RECT  2.704 23.04 2.765 25.224 ;
     RECT  2.704 26.784 2.765 28.728 ;
     RECT  2.704 30.864 2.765 30.888 ;
     RECT  2.704 15.312 2.801 15.336 ;
     RECT  2.765 23.712 2.837 25.224 ;
     RECT  2.704 21.456 2.909 21.48 ;
     RECT  2.765 26.784 3.017 28.584 ;
     RECT  2.837 23.712 3.089 24.936 ;
     RECT  3.089 23.712 3.233 23.736 ;
     RECT  3.089 24.912 3.233 24.936 ;
     RECT  3.017 26.784 3.269 27.672 ;
     RECT  3.269 26.784 3.377 26.808 ;
     RECT  4.093 23.184 4.345 23.208 ;
     RECT  4.345 22.752 4.457 23.208 ;
     RECT  4.457 22.752 4.601 22.776 ;
     RECT  7.808 2.148 7.912 49.692 ;
     RECT  7.912 2.418 8.104 49.422 ;
     RECT  13.208 2.148 13.312 49.692 ;
     RECT  13.312 2.418 13.504 49.422 ;
     RECT  15.217 47.808 15.788 47.832 ;
     RECT  15.733 49.488 15.788 49.512 ;
     RECT  15.788 47.808 15.875 49.512 ;
     RECT  15.875 47.808 16.981 47.832 ;
     RECT  16.981 47.808 17.021 47.928 ;
     RECT  16.124 49.536 17.029 49.56 ;
     RECT  17.029 49.488 17.372 49.56 ;
     RECT  17.372 49.296 17.629 49.56 ;
     RECT  17.021 47.904 18.385 47.928 ;
     RECT  17.629 48.96 18.385 49.56 ;
     RECT  15.301 36.816 18.608 36.84 ;
     RECT  18.385 47.904 18.608 49.56 ;
     RECT  18.608 2.148 18.712 49.692 ;
     RECT  18.712 2.418 18.737 49.692 ;
     RECT  18.737 2.418 18.821 49.8 ;
     RECT  18.821 2.418 18.904 49.56 ;
     RECT  18.904 47.712 19.043 49.56 ;
     RECT  19.043 48.72 19.145 49.56 ;
     RECT  19.043 47.712 19.173 47.736 ;
     RECT  19.145 48.768 20.153 49.56 ;
     RECT  20.153 49.008 20.572 49.56 ;
     RECT  20.572 49.008 20.963 49.272 ;
     RECT  20.963 49.248 21.395 49.272 ;
     RECT  21.781 49.536 22.025 49.56 ;
     RECT  22.117 27.792 22.204 27.816 ;
     RECT  22.645 49.008 22.778 49.08 ;
     RECT  22.778 49.056 22.889 49.08 ;
     RECT  22.172 50.736 23.123 50.76 ;
     RECT  23.353 49.536 23.941 49.56 ;
     RECT  18.904 36.816 24.008 36.84 ;
     RECT  18.904 40.848 24.008 40.872 ;
     RECT  23.941 49.536 24.008 49.848 ;
     RECT  24.008 2.148 24.028 49.848 ;
     RECT  24.028 2.148 24.112 49.692 ;
     RECT  24.112 2.418 24.304 49.56 ;
     RECT  24.304 49.344 24.509 49.56 ;
     RECT  24.509 49.536 25.283 49.56 ;
     RECT  26.06 49.008 26.147 49.032 ;
     RECT  25.513 50.736 26.593 50.76 ;
     RECT  24.304 40.848 26.701 40.872 ;
     RECT  26.593 50.736 27.011 51.672 ;
     RECT  26.701 40.656 27.029 40.872 ;
     RECT  27.011 50.736 27.443 50.76 ;
     RECT  27.781 49.536 27.875 49.56 ;
     RECT  29.077 49.536 29.329 49.56 ;
     RECT  24.304 36.816 29.408 36.84 ;
     RECT  27.029 40.656 29.408 40.68 ;
     RECT  29.329 49.536 29.408 49.8 ;
     RECT  29.408 2.148 29.512 49.8 ;
     RECT  29.512 2.418 29.603 49.8 ;
     RECT  29.603 2.418 29.704 49.56 ;
     RECT  29.704 36.816 31.205 36.84 ;
     RECT  31.484 36.768 31.571 36.792 ;
     RECT  29.704 40.656 31.571 40.68 ;
     RECT  29.704 49.536 31.763 49.56 ;
     RECT  31.777 50.736 32.195 50.76 ;
     RECT  33.397 49.536 33.491 49.56 ;
     RECT  31.525 33.312 34.808 33.336 ;
     RECT  33.877 49.488 34.808 49.512 ;
     RECT  34.808 2.148 34.912 49.692 ;
     RECT  34.912 2.418 35.104 49.422 ;
     RECT  35.104 49.344 35.705 49.368 ;
     RECT  35.104 33.312 35.741 33.336 ;
     RECT  35.809 50.736 36.515 50.76 ;
     RECT  36.457 33.264 40.208 33.288 ;
     RECT  40.208 2.148 40.312 49.692 ;
     RECT  40.312 2.418 40.504 49.422 ;
     RECT  41.749 26.208 42.317 26.232 ;
     RECT  42.317 26.208 42.332 26.856 ;
     RECT  42.332 26.208 42.371 27.336 ;
     RECT  42.371 26.736 42.419 27.336 ;
     RECT  40.504 33.264 42.419 33.288 ;
     RECT  42.419 26.736 43.945 26.76 ;
     RECT  43.945 26.256 43.985 26.76 ;
     RECT  43.985 26.256 45.608 26.28 ;
     RECT  45.608 2.148 45.712 49.692 ;
     RECT  45.712 2.418 45.904 49.422 ;
     RECT  45.904 26.256 46.613 26.328 ;
     RECT  46.613 26.256 47.125 26.28 ;
     RECT  47.105 24.48 47.189 24.504 ;
     RECT  47.125 26.016 47.212 26.28 ;
     RECT  47.149 27.36 47.233 27.384 ;
     RECT  47.212 26.256 47.253 26.28 ;
     RECT  49.813 24.144 50.173 24.168 ;
     RECT  50.137 25.44 50.173 25.464 ;
     RECT  50.173 24.144 50.677 25.464 ;
     RECT  50.641 27.168 50.677 27.192 ;
     RECT  50.677 24.144 51.804 27.624 ;
    LAYER M5 ;
     RECT  2.4 2.137 2.52 2.151 ;
     RECT  7.8 2.137 7.92 2.151 ;
     RECT  13.2 2.137 13.32 2.151 ;
     RECT  18.6 2.137 18.72 2.151 ;
     RECT  24 2.137 24.12 2.151 ;
     RECT  29.4 2.137 29.52 2.151 ;
     RECT  34.8 2.137 34.92 2.151 ;
     RECT  40.2 2.137 40.32 2.151 ;
     RECT  45.6 2.137 45.72 2.151 ;
     RECT  2.4 2.151 2.712 25.045 ;
     RECT  47.136 24.469 47.16 26.051 ;
     RECT  42.336 26.197 42.36 26.867 ;
     RECT  47.184 26.245 47.208 27.395 ;
     RECT  2.304 25.045 2.712 28.213 ;
     RECT  2.304 28.213 2.904 28.595 ;
     RECT  2.304 28.595 2.712 30.995 ;
     RECT  42.384 27.301 42.408 33.299 ;
     RECT  31.536 33.301 31.56 40.691 ;
     RECT  18.6 2.151 18.912 40.837 ;
     RECT  22.128 27.781 22.152 40.883 ;
     RECT  18.6 40.837 19.128 47.747 ;
     RECT  15.312 36.805 15.336 47.797 ;
     RECT  20.928 48.997 20.952 49.237 ;
     RECT  24 2.151 24.312 49.333 ;
     RECT  34.8 2.151 35.112 49.333 ;
     RECT  17.424 47.893 17.448 49.477 ;
     RECT  18.6 47.747 19.032 49.477 ;
     RECT  34.8 49.333 35.64 49.477 ;
     RECT  15.312 47.797 15.864 49.525 ;
     RECT  17.04 49.477 17.448 49.525 ;
     RECT  18.6 49.477 19.224 49.525 ;
     RECT  20.928 49.237 21.384 49.525 ;
     RECT  22.656 48.997 22.68 49.525 ;
     RECT  24 49.333 24.408 49.525 ;
     RECT  26.112 48.997 26.136 49.525 ;
     RECT  29.4 2.151 29.712 49.525 ;
     RECT  33.888 49.477 35.64 49.525 ;
     RECT  2.4 30.995 2.712 49.689 ;
     RECT  7.8 2.151 8.112 49.689 ;
     RECT  13.2 2.151 13.512 49.689 ;
     RECT  40.2 2.151 40.512 49.689 ;
     RECT  45.6 2.151 45.912 49.689 ;
     RECT  2.4 49.689 2.52 49.703 ;
     RECT  7.8 49.689 7.92 49.703 ;
     RECT  13.2 49.689 13.32 49.703 ;
     RECT  33.456 49.525 35.64 49.703 ;
     RECT  40.2 49.689 40.32 49.703 ;
     RECT  45.6 49.689 45.72 49.703 ;
     RECT  15.312 49.525 26.136 50.725 ;
     RECT  27.84 49.525 27.864 50.725 ;
     RECT  31.296 49.525 31.752 50.725 ;
     RECT  35.616 49.703 35.64 50.725 ;
     RECT  15.312 50.725 27.864 51.792 ;
     RECT  29.136 49.525 30.024 51.792 ;
     RECT  31.296 50.725 32.184 51.792 ;
     RECT  33.456 49.703 34.344 51.792 ;
     RECT  35.616 50.725 36.504 51.792 ;
     RECT  45.912 24.469 47.136 26.051 ;
     RECT  45.912 26.051 47.16 26.245 ;
     RECT  45.912 26.245 47.184 27.395 ;
     RECT  17.448 47.893 18.6 49.525 ;
     RECT  22.68 48.997 24 49.525 ;
     RECT  21.384 49.237 22.656 49.525 ;
     RECT  15.864 49.477 17.04 49.525 ;
     RECT  27.864 49.525 29.136 51.708 ;
     RECT  30.024 49.525 31.296 51.708 ;
     RECT  34.344 49.703 35.616 51.708 ;
     RECT  32.184 50.725 33.456 51.708 ;
     RECT  27.912 51.708 28.224 51.792 ;
     RECT  28.344 51.708 28.656 51.792 ;
     RECT  28.776 51.708 29.088 51.792 ;
     RECT  30.072 51.708 30.384 51.792 ;
     RECT  30.504 51.708 30.816 51.792 ;
     RECT  30.936 51.708 31.248 51.792 ;
     RECT  32.232 51.708 32.544 51.792 ;
     RECT  32.664 51.708 32.976 51.792 ;
     RECT  33.096 51.708 33.408 51.792 ;
     RECT  34.392 51.708 34.704 51.792 ;
     RECT  34.824 51.708 35.136 51.792 ;
     RECT  35.256 51.708 35.568 51.792 ;
  END
END dsfd_vm_static_read_v2
END LIBRARY
